VERSION 5.8 ;
BUSBITCHARS "[]" ;
DIVIDERCHAR "/" ;
CLEARANCEMEASURE EUCLIDEAN ;

SITE coresite_DH_P
    SIZE 0.0450 BY 0.2880 ;
    CLASS CORE ;
    SYMMETRY X Y ;
END coresite_DH_P

SITE coresite_DH_N
    SIZE 0.0450 BY 0.2880 ;
    CLASS CORE ;
    SYMMETRY X Y ;
END coresite_DH_N

SITE coresite
    SIZE 0.0450 BY 0.1440 ;
    CLASS CORE ;
    SYMMETRY X Y ;
END coresite

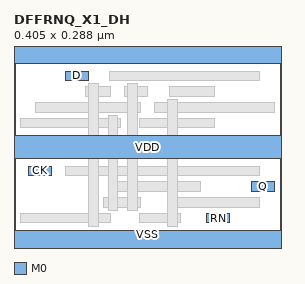
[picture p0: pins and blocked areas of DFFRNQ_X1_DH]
MACRO DFFRNQ_X1_DH
  CLASS CORE ;
  ORIGIN 0 0 ;
  FOREIGN DFFRNQ_X1_DH 0 0 ;
  SIZE 0.4050 BY 0.2880 ;
  SYMMETRY X Y ;
  SITE coresite_DH_N ;
  PIN D
    DIRECTION INPUT ;
    USE SIGNAL ;
    PORT
      LAYER M0 ;
        RECT 0.0780 0.2590 0.1125 0.2450 ;
    END
  END D
  PIN CK
    DIRECTION INPUT ;
    USE SIGNAL ;
    PORT
      LAYER M0 ;
        RECT 0.0225 0.1150 0.0570 0.1010 ;
    END
  END CK
  PIN Q
    DIRECTION OUTPUT ;
    USE SIGNAL ;
    PORT
      LAYER M0 ;
        RECT 0.3600 0.0910 0.3945 0.0770 ;
    END
  END Q
  PIN RN
    DIRECTION INPUT ;
    USE SIGNAL ;
    PORT
      LAYER M0 ;
        RECT 0.2925 0.0430 0.3270 0.0290 ;
    END
  END RN
  PIN VDD
    DIRECTION INOUT ;
    USE POWER ;
    SHAPE ABUTMENT ;
    PORT
      LAYER M0 ;
        RECT 0.0000 0.1260 0.4050 0.1620 ;
    END
  END VDD
  PIN VSS
    DIRECTION INOUT ;
    USE GROUND ;
    SHAPE ABUTMENT ;
    PORT
      LAYER M0 ;
        RECT 0.0000 0.2700 0.4050 0.3060 ;
        RECT 0.0000 -0.0180 0.4050 0.0180 ;
    END
  END VSS
  OBS
      LAYER V0 ;
        RECT 0.2330 0.1970 0.2470 0.2110 ;
        RECT 0.2330 0.0290 0.2470 0.0430 ;
        RECT 0.1730 0.2210 0.1870 0.2350 ;
        RECT 0.1730 0.0530 0.1870 0.0670 ;
        RECT 0.1430 0.1730 0.1570 0.1870 ;
        RECT 0.1430 0.0530 0.1570 0.0670 ;
        RECT 0.1130 0.1970 0.1270 0.2110 ;
        RECT 0.1130 0.2210 0.1270 0.2350 ;
        RECT 0.1130 0.0290 0.1270 0.0430 ;
      LAYER M0 ;
        RECT 0.1455 0.2450 0.3720 0.2590 ;
        RECT 0.2355 0.2210 0.3045 0.2350 ;
        RECT 0.1680 0.2210 0.2025 0.2350 ;
        RECT 0.1080 0.2210 0.1470 0.2350 ;
        RECT 0.2130 0.1970 0.3945 0.2110 ;
        RECT 0.0330 0.1970 0.1920 0.2110 ;
        RECT 0.1905 0.1730 0.3045 0.1870 ;
        RECT 0.0105 0.1730 0.1620 0.1870 ;
        RECT 0.0780 0.1010 0.3720 0.1150 ;
        RECT 0.1455 0.0770 0.2820 0.0910 ;
        RECT 0.2355 0.0530 0.3720 0.0670 ;
        RECT 0.1350 0.0530 0.1920 0.0670 ;
        RECT 0.1905 0.0290 0.2520 0.0430 ;
        RECT 0.0105 0.0290 0.1470 0.0430 ;
      LAYER M1 ;
        RECT 0.1725 0.2400 0.1875 0.0480 ;
        RECT 0.1125 0.2400 0.1275 0.0240 ;
        RECT 0.2325 0.2160 0.2475 0.0240 ;
        RECT 0.1425 0.1920 0.1575 0.0480 ;
  END
END DFFRNQ_X1_DH

END LIBRARY
